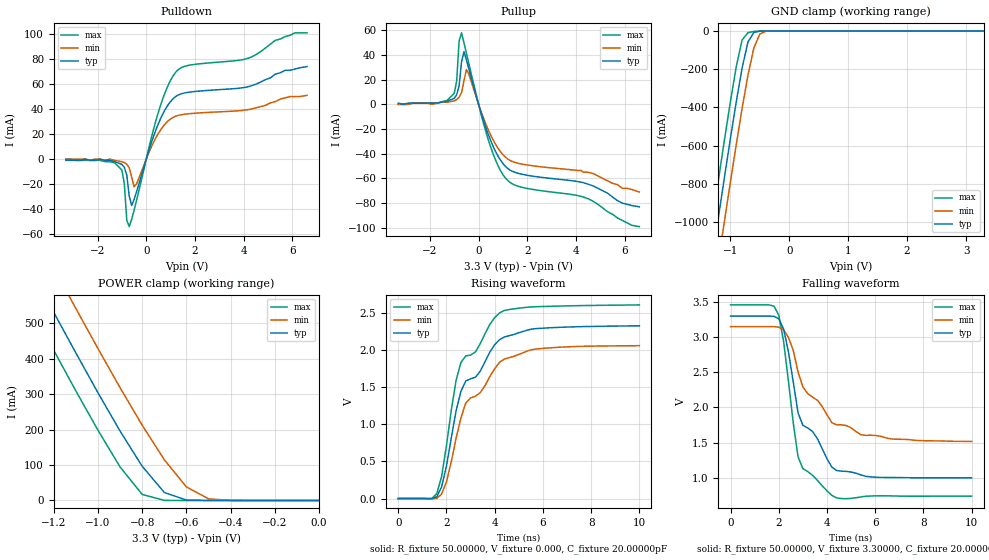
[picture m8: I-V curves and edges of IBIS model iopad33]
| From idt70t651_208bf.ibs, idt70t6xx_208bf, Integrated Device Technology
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|   Model iopad33
[Model]   iopad33
Model_type   I/O
Polarity   Non-Inverting
Enable   Active-Low
Vinl =  0.80000V
Vinh =  2.00000V
Vmeas =  1.50000V
C_comp   4.50000pF   4.50000pF   4.50000pF
[Temperature Range]   25.00000   100.00000   -40.00000
[Voltage Range]   3.30000V   3.10000V   3.50000V
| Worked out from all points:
|   slope of the pulldown table from 0 to 0.495 V, typ, clamps not added: 17.5 ohm
|   slope of the pullup table from 0 to 0.495 V, typ, clamps not added: 16.9 ohm
|   GND clamp passes 1 mA (typ) near -0.50 V on its own axis
|   POWER clamp passes 1 mA (typ) near -0.59 V on its own axis
|   rising waveform, R_fixture 50.00000, V_fixture 0.000, C_fixture 20.00000pF: 20-80 % time 1.61ns typ, 1.67ns min, 1.49ns max; typ from 0 V to 2.33 V
|   falling waveform, R_fixture 50.00000, V_fixture 3.30000, C_fixture 20.00000pF: 20-80 % time 1.36ns typ, 1.5ns min, 608ps max; typ from 3.3 V to 1 V
[Pulldown]
| voltage   I(typ)   I(min)   I(max)
-3.3V     -1mA       0A         0A
-1.5V     -1mA       0A         -2mA
-1V       -4.2mA     -2.1mA     -8.8mA
-900mV    -6.6mA     -2.8mA     -19.7mA
-800mV    -12.8mA    -4.1mA     -48.76mA
-700mV    -29.43mA   -7mA       -53.96mA
-600mV    -37.03mA   -14.17mA   -48.13mA
-500mV    -32.29mA   -22.11mA   -40.89mA
500mV     28.49mA    20.63mA    37.7mA
1.2V      49.93mA    34.24mA    69.32mA
4.1V      57.54mA    39.4mA     80.21mA
6.6V      74mA       51mA       101mA
[Pullup]
| voltage   I(typ)   I(min)   I(max)
-3.3V     1mA        0A         0A
-1.7V     1mA        1mA        1mA
-1V       4.9mA      2.9mA      8.9mA
-900mV    7.8mA      3.9mA      18.89mA
-800mV    14.94mA    5.7mA      51.34mA
-700mV    34.57mA    9.6mA      57.95mA
-600mV    42.62mA    19.25mA    49.81mA
-500mV    36.06mA    28.2mA     41.39mA
400mV     -24.39mA   -20.73mA   -28.72mA
1.1V      -50.2mA    -42.72mA   -59.63mA
4.3V      -63.4mA    -55mA      -75.04mA
6.6V      -83mA      -71mA      -99mA
[GND_clamp]
| voltage   I(typ)   I(min)   I(max)
-3.3V     -5.469A    -5.686A    -5.287A
-1.4V     -1.389A    -1.618A    -1.194A
-1.3V     -1.179A    -1.409A    -984.5mA
-1.2V     -972.3mA   -1.201A    -776.5mA
-1.1V     -767.3mA   -996.6mA   -571.8mA
-900mV    -372.8mA   -596.6mA   -188.1mA
-800mV    -194.3mA   -406.4mA   -47.16mA
-700mV    -57.22mA   -230.7mA   -8.4mA
-600mV    -7.393mA   -88.33mA   -2.169mA
-500mV    -1.009mA   -16.09mA   -229.2uA
-400mV    -92.71uA   -1.476mA   -9.663uA
3.3V      525.2pA    638.3nA    1.93pA
[POWER_clamp]
| voltage   I(typ)   I(min)   I(max)
-3.3V     3.039A     3.158A     2.94A
-1.4V     762.6mA    887.5mA    656.3mA
-1.3V     645.8mA    771mA      539.1mA
-1.2V     529.9mA    655.3mA    422.9mA
-1.1V     415.5mA    540.8mA    308.5mA
-1V       303.3mA    427.9mA    197.7mA
-900mV    195.4mA    317.6mA    94.25mA
-800mV    96.26mA    211.9mA    16.94mA
-700mV    22.53mA    114.6mA    304.8uA
-600mV    1.137mA    38.18mA    3.7uA
-500mV    27.9uA     4.729mA    76.79nA
0V        525.2pA    48.85nA    2.01pA
[Ramp]
| variable   typ   min   max
dV/dt_r   1.40040/0.58697n   1.23900/0.67661n   1.57020/0.47445n
dV/dt_f   1.38174/0.37674n   1.05360/0.46010n   1.62528/0.29291n
R_load = 50.00000
[Rising Waveform]
R_fixture = 50.00000
V_fixture = 0.000
C_fixture = 20.00000pF
R_dut = 100.00000m
L_dut = 12.00000nH
C_dut = 2.80000pF
| time   V(typ)   V(min)   V(max)
0s        0V         0V         0V
1.6ns     24.5mV     2.842mV    66.77mV
2ns       436mV      223.8mV    711.9mV
2.4ns     1.183V     812.1mV    1.593V
2.6ns     1.444V     1.086V     1.834V
2.8ns     1.584V     1.287V     1.922V
3.2ns     1.635V     1.379V     1.976V
4.2ns     2.14V      1.837V     2.501V
5.6ns     2.288V     2.011V     2.584V
10ns      2.328V     2.061V     2.61V
[Falling Waveform]
R_fixture = 50.00000
V_fixture = 3.30000
C_fixture = 20.00000pF
R_dut = 100.00000m
L_dut = 12.00000nH
C_dut = 2.80000pF
| time   V(typ)   V(min)   V(max)
0s        3.3V       3.15V      3.459V
1.6ns     3.3V       3.15V      3.459V
2ns       3.264V     3.143V     3.314V
2.4ns     2.794V     2.998V     2.375V
2.8ns     1.922V     2.502V     1.297V
3ns       1.746V     2.293V     1.13V
3.4ns     1.658V     2.147V     1.035V
4.2ns     1.151V     1.784V     749.5mV
6.6ns     1.004V     1.556V     742.1mV
10ns      999.7mV    1.517V     738.2mV
